VERSION 5.7 ;
BUSBITCHARS "[]" ;
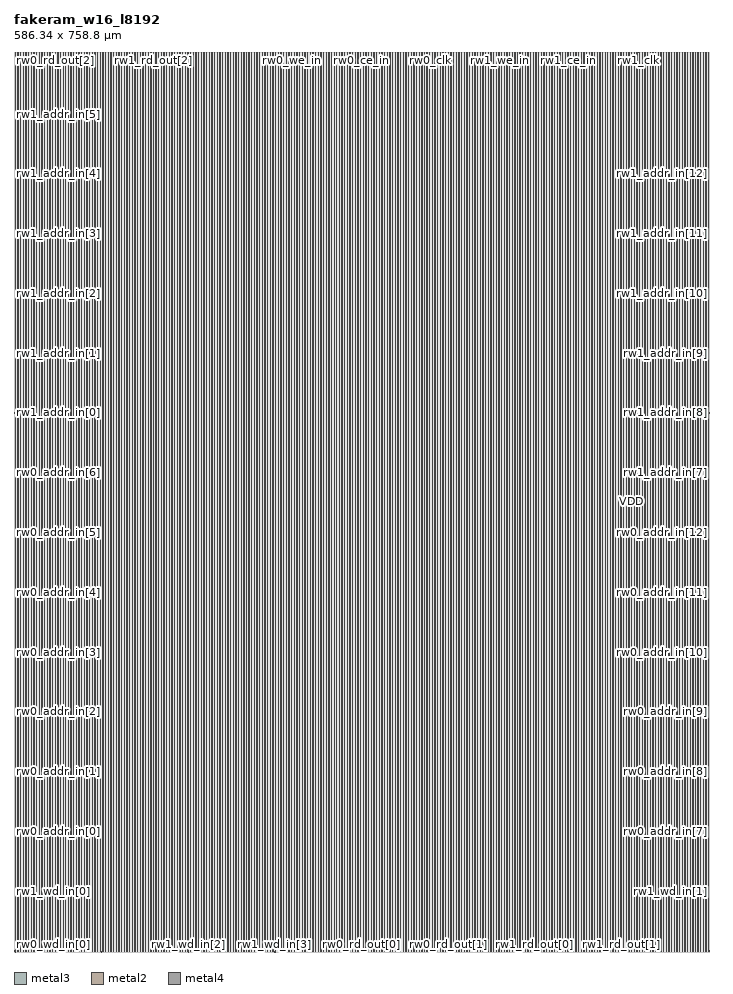
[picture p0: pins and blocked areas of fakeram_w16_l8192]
MACRO fakeram_w16_l8192
  FOREIGN fakeram_w16_l8192 0 0 ;
  SYMMETRY X Y R90 ;
  SIZE 586.340 BY 758.800 ;
  CLASS BLOCK ;
  PIN rw0_wd_in[0]
    DIRECTION INPUT ;
    USE SIGNAL ;
    SHAPE ABUTMENT ;
    PORT
      LAYER metal3 ;
      RECT 0.000 0.805 0.210 0.875 ;
    END
  END rw0_wd_in[0]
  PIN rw0_wd_in[1]
    DIRECTION INPUT ;
    USE SIGNAL ;
    SHAPE ABUTMENT ;
    PORT
      LAYER metal3 ;
      RECT 586.130 0.805 586.340 0.875 ;
    END
  END rw0_wd_in[1]
  PIN rw0_wd_in[2]
    DIRECTION INPUT ;
    USE SIGNAL ;
    SHAPE ABUTMENT ;
    PORT
      LAYER metal2 ;
      RECT 1.105 0.000 1.175 0.210 ;
    END
  END rw0_wd_in[2]
  PIN rw0_wd_in[3]
    DIRECTION INPUT ;
    USE SIGNAL ;
    SHAPE ABUTMENT ;
    PORT
      LAYER metal2 ;
      RECT 74.065 0.000 74.135 0.210 ;
    END
  END rw0_wd_in[3]
  PIN rw1_wd_in[0]
    DIRECTION INPUT ;
    USE SIGNAL ;
    SHAPE ABUTMENT ;
    PORT
      LAYER metal3 ;
      RECT 0.000 51.205 0.210 51.275 ;
    END
  END rw1_wd_in[0]
  PIN rw1_wd_in[1]
    DIRECTION INPUT ;
    USE SIGNAL ;
    SHAPE ABUTMENT ;
    PORT
      LAYER metal3 ;
      RECT 586.130 51.205 586.340 51.275 ;
    END
  END rw1_wd_in[1]
  PIN rw1_wd_in[2]
    DIRECTION INPUT ;
    USE SIGNAL ;
    SHAPE ABUTMENT ;
    PORT
      LAYER metal2 ;
      RECT 147.025 0.000 147.095 0.210 ;
    END
  END rw1_wd_in[2]
  PIN rw1_wd_in[3]
    DIRECTION INPUT ;
    USE SIGNAL ;
    SHAPE ABUTMENT ;
    PORT
      LAYER metal2 ;
      RECT 219.985 0.000 220.055 0.210 ;
    END
  END rw1_wd_in[3]
  PIN rw0_rd_out[0]
    DIRECTION OUTPUT ;
    USE SIGNAL ;
    SHAPE ABUTMENT ;
    PORT
      LAYER metal2 ;
      RECT 292.945 0.000 293.015 0.210 ;
    END
  END rw0_rd_out[0]
  PIN rw0_rd_out[1]
    DIRECTION OUTPUT ;
    USE SIGNAL ;
    SHAPE ABUTMENT ;
    PORT
      LAYER metal2 ;
      RECT 365.905 0.000 365.975 0.210 ;
    END
  END rw0_rd_out[1]
  PIN rw0_rd_out[2]
    DIRECTION OUTPUT ;
    USE SIGNAL ;
    SHAPE ABUTMENT ;
    PORT
      LAYER metal2 ;
      RECT 1.105 758.590 1.175 758.800 ;
    END
  END rw0_rd_out[2]
  PIN rw0_rd_out[3]
    DIRECTION OUTPUT ;
    USE SIGNAL ;
    SHAPE ABUTMENT ;
    PORT
      LAYER metal2 ;
      RECT 59.435 758.590 59.505 758.800 ;
    END
  END rw0_rd_out[3]
  PIN rw1_rd_out[0]
    DIRECTION OUTPUT ;
    USE SIGNAL ;
    SHAPE ABUTMENT ;
    PORT
      LAYER metal2 ;
      RECT 438.865 0.000 438.935 0.210 ;
    END
  END rw1_rd_out[0]
  PIN rw1_rd_out[1]
    DIRECTION OUTPUT ;
    USE SIGNAL ;
    SHAPE ABUTMENT ;
    PORT
      LAYER metal2 ;
      RECT 511.825 0.000 511.895 0.210 ;
    END
  END rw1_rd_out[1]
  PIN rw1_rd_out[2]
    DIRECTION OUTPUT ;
    USE SIGNAL ;
    SHAPE ABUTMENT ;
    PORT
      LAYER metal2 ;
      RECT 117.765 758.590 117.835 758.800 ;
    END
  END rw1_rd_out[2]
  PIN rw1_rd_out[3]
    DIRECTION OUTPUT ;
    USE SIGNAL ;
    SHAPE ABUTMENT ;
    PORT
      LAYER metal2 ;
      RECT 176.095 758.590 176.165 758.800 ;
    END
  END rw1_rd_out[3]
  PIN rw0_addr_in[0]
    DIRECTION INPUT ;
    USE SIGNAL ;
    SHAPE ABUTMENT ;
    PORT
      LAYER metal3 ;
      RECT 0.000 101.605 0.210 101.675 ;
    END
  END rw0_addr_in[0]
  PIN rw0_addr_in[1]
    DIRECTION INPUT ;
    USE SIGNAL ;
    SHAPE ABUTMENT ;
    PORT
      LAYER metal3 ;
      RECT 0.000 152.005 0.210 152.075 ;
    END
  END rw0_addr_in[1]
  PIN rw0_addr_in[2]
    DIRECTION INPUT ;
    USE SIGNAL ;
    SHAPE ABUTMENT ;
    PORT
      LAYER metal3 ;
      RECT 0.000 202.405 0.210 202.475 ;
    END
  END rw0_addr_in[2]
  PIN rw0_addr_in[3]
    DIRECTION INPUT ;
    USE SIGNAL ;
    SHAPE ABUTMENT ;
    PORT
      LAYER metal3 ;
      RECT 0.000 252.805 0.210 252.875 ;
    END
  END rw0_addr_in[3]
  PIN rw0_addr_in[4]
    DIRECTION INPUT ;
    USE SIGNAL ;
    SHAPE ABUTMENT ;
    PORT
      LAYER metal3 ;
      RECT 0.000 303.205 0.210 303.275 ;
    END
  END rw0_addr_in[4]
  PIN rw0_addr_in[5]
    DIRECTION INPUT ;
    USE SIGNAL ;
    SHAPE ABUTMENT ;
    PORT
      LAYER metal3 ;
      RECT 0.000 353.605 0.210 353.675 ;
    END
  END rw0_addr_in[5]
  PIN rw0_addr_in[6]
    DIRECTION INPUT ;
    USE SIGNAL ;
    SHAPE ABUTMENT ;
    PORT
      LAYER metal3 ;
      RECT 0.000 404.005 0.210 404.075 ;
    END
  END rw0_addr_in[6]
  PIN rw0_addr_in[7]
    DIRECTION INPUT ;
    USE SIGNAL ;
    SHAPE ABUTMENT ;
    PORT
      LAYER metal3 ;
      RECT 586.130 101.605 586.340 101.675 ;
    END
  END rw0_addr_in[7]
  PIN rw0_addr_in[8]
    DIRECTION INPUT ;
    USE SIGNAL ;
    SHAPE ABUTMENT ;
    PORT
      LAYER metal3 ;
      RECT 586.130 152.005 586.340 152.075 ;
    END
  END rw0_addr_in[8]
  PIN rw0_addr_in[9]
    DIRECTION INPUT ;
    USE SIGNAL ;
    SHAPE ABUTMENT ;
    PORT
      LAYER metal3 ;
      RECT 586.130 202.405 586.340 202.475 ;
    END
  END rw0_addr_in[9]
  PIN rw0_addr_in[10]
    DIRECTION INPUT ;
    USE SIGNAL ;
    SHAPE ABUTMENT ;
    PORT
      LAYER metal3 ;
      RECT 586.130 252.805 586.340 252.875 ;
    END
  END rw0_addr_in[10]
  PIN rw0_addr_in[11]
    DIRECTION INPUT ;
    USE SIGNAL ;
    SHAPE ABUTMENT ;
    PORT
      LAYER metal3 ;
      RECT 586.130 303.205 586.340 303.275 ;
    END
  END rw0_addr_in[11]
  PIN rw0_addr_in[12]
    DIRECTION INPUT ;
    USE SIGNAL ;
    SHAPE ABUTMENT ;
    PORT
      LAYER metal3 ;
      RECT 586.130 353.605 586.340 353.675 ;
    END
  END rw0_addr_in[12]
  PIN rw1_addr_in[0]
    DIRECTION INPUT ;
    USE SIGNAL ;
    SHAPE ABUTMENT ;
    PORT
      LAYER metal3 ;
      RECT 0.000 454.405 0.210 454.475 ;
    END
  END rw1_addr_in[0]
  PIN rw1_addr_in[1]
    DIRECTION INPUT ;
    USE SIGNAL ;
    SHAPE ABUTMENT ;
    PORT
      LAYER metal3 ;
      RECT 0.000 504.805 0.210 504.875 ;
    END
  END rw1_addr_in[1]
  PIN rw1_addr_in[2]
    DIRECTION INPUT ;
    USE SIGNAL ;
    SHAPE ABUTMENT ;
    PORT
      LAYER metal3 ;
      RECT 0.000 555.205 0.210 555.275 ;
    END
  END rw1_addr_in[2]
  PIN rw1_addr_in[3]
    DIRECTION INPUT ;
    USE SIGNAL ;
    SHAPE ABUTMENT ;
    PORT
      LAYER metal3 ;
      RECT 0.000 605.605 0.210 605.675 ;
    END
  END rw1_addr_in[3]
  PIN rw1_addr_in[4]
    DIRECTION INPUT ;
    USE SIGNAL ;
    SHAPE ABUTMENT ;
    PORT
      LAYER metal3 ;
      RECT 0.000 656.005 0.210 656.075 ;
    END
  END rw1_addr_in[4]
  PIN rw1_addr_in[5]
    DIRECTION INPUT ;
    USE SIGNAL ;
    SHAPE ABUTMENT ;
    PORT
      LAYER metal3 ;
      RECT 0.000 706.405 0.210 706.475 ;
    END
  END rw1_addr_in[5]
  PIN rw1_addr_in[6]
    DIRECTION INPUT ;
    USE SIGNAL ;
    SHAPE ABUTMENT ;
    PORT
      LAYER metal3 ;
      RECT 0.000 756.805 0.210 756.875 ;
    END
  END rw1_addr_in[6]
  PIN rw1_addr_in[7]
    DIRECTION INPUT ;
    USE SIGNAL ;
    SHAPE ABUTMENT ;
    PORT
      LAYER metal3 ;
      RECT 586.130 404.005 586.340 404.075 ;
    END
  END rw1_addr_in[7]
  PIN rw1_addr_in[8]
    DIRECTION INPUT ;
    USE SIGNAL ;
    SHAPE ABUTMENT ;
    PORT
      LAYER metal3 ;
      RECT 586.130 454.405 586.340 454.475 ;
    END
  END rw1_addr_in[8]
  PIN rw1_addr_in[9]
    DIRECTION INPUT ;
    USE SIGNAL ;
    SHAPE ABUTMENT ;
    PORT
      LAYER metal3 ;
      RECT 586.130 504.805 586.340 504.875 ;
    END
  END rw1_addr_in[9]
  PIN rw1_addr_in[10]
    DIRECTION INPUT ;
    USE SIGNAL ;
    SHAPE ABUTMENT ;
    PORT
      LAYER metal3 ;
      RECT 586.130 555.205 586.340 555.275 ;
    END
  END rw1_addr_in[10]
  PIN rw1_addr_in[11]
    DIRECTION INPUT ;
    USE SIGNAL ;
    SHAPE ABUTMENT ;
    PORT
      LAYER metal3 ;
      RECT 586.130 605.605 586.340 605.675 ;
    END
  END rw1_addr_in[11]
  PIN rw1_addr_in[12]
    DIRECTION INPUT ;
    USE SIGNAL ;
    SHAPE ABUTMENT ;
    PORT
      LAYER metal3 ;
      RECT 586.130 656.005 586.340 656.075 ;
    END
  END rw1_addr_in[12]
  PIN rw0_we_in
    DIRECTION INPUT ;
    USE SIGNAL ;
    SHAPE ABUTMENT ;
    PORT
      LAYER metal2 ;
      RECT 234.425 758.590 234.495 758.800 ;
    END
  END rw0_we_in
  PIN rw0_ce_in
    DIRECTION INPUT ;
    USE SIGNAL ;
    SHAPE ABUTMENT ;
    PORT
      LAYER metal2 ;
      RECT 292.755 758.590 292.825 758.800 ;
    END
  END rw0_ce_in
  PIN rw0_clk
    DIRECTION INPUT ;
    USE SIGNAL ;
    SHAPE ABUTMENT ;
    PORT
      LAYER metal2 ;
      RECT 351.085 758.590 351.155 758.800 ;
    END
  END rw0_clk
  PIN rw1_we_in
    DIRECTION INPUT ;
    USE SIGNAL ;
    SHAPE ABUTMENT ;
    PORT
      LAYER metal2 ;
      RECT 409.415 758.590 409.485 758.800 ;
    END
  END rw1_we_in
  PIN rw1_ce_in
    DIRECTION INPUT ;
    USE SIGNAL ;
    SHAPE ABUTMENT ;
    PORT
      LAYER metal2 ;
      RECT 467.745 758.590 467.815 758.800 ;
    END
  END rw1_ce_in
  PIN rw1_clk
    DIRECTION INPUT ;
    USE SIGNAL ;
    SHAPE ABUTMENT ;
    PORT
      LAYER metal2 ;
      RECT 526.075 758.590 526.145 758.800 ;
    END
  END rw1_clk
  PIN VSS
    DIRECTION INOUT ;
    USE GROUND ;
    PORT
      LAYER metal4 ;
      RECT 1.000 0.840 1.280 757.960 ;
      RECT 3.240 0.840 3.520 757.960 ;
      RECT 5.480 0.840 5.760 757.960 ;
      RECT 7.720 0.840 8.000 757.960 ;
      RECT 9.960 0.840 10.240 757.960 ;
      RECT 12.200 0.840 12.480 757.960 ;
      RECT 14.440 0.840 14.720 757.960 ;
      RECT 16.680 0.840 16.960 757.960 ;
      RECT 18.920 0.840 19.200 757.960 ;
      RECT 21.160 0.840 21.440 757.960 ;
      RECT 23.400 0.840 23.680 757.960 ;
      RECT 25.640 0.840 25.920 757.960 ;
      RECT 27.880 0.840 28.160 757.960 ;
      RECT 30.120 0.840 30.400 757.960 ;
      RECT 32.360 0.840 32.640 757.960 ;
      RECT 34.600 0.840 34.880 757.960 ;
      RECT 36.840 0.840 37.120 757.960 ;
      RECT 39.080 0.840 39.360 757.960 ;
      RECT 41.320 0.840 41.600 757.960 ;
      RECT 43.560 0.840 43.840 757.960 ;
      RECT 45.800 0.840 46.080 757.960 ;
      RECT 48.040 0.840 48.320 757.960 ;
      RECT 50.280 0.840 50.560 757.960 ;
      RECT 52.520 0.840 52.800 757.960 ;
      RECT 54.760 0.840 55.040 757.960 ;
      RECT 57.000 0.840 57.280 757.960 ;
      RECT 59.240 0.840 59.520 757.960 ;
      RECT 61.480 0.840 61.760 757.960 ;
      RECT 63.720 0.840 64.000 757.960 ;
      RECT 65.960 0.840 66.240 757.960 ;
      RECT 68.200 0.840 68.480 757.960 ;
      RECT 70.440 0.840 70.720 757.960 ;
      RECT 72.680 0.840 72.960 757.960 ;
      RECT 74.920 0.840 75.200 757.960 ;
      RECT 77.160 0.840 77.440 757.960 ;
      RECT 79.400 0.840 79.680 757.960 ;
      RECT 81.640 0.840 81.920 757.960 ;
      RECT 83.880 0.840 84.160 757.960 ;
      RECT 86.120 0.840 86.400 757.960 ;
      RECT 88.360 0.840 88.640 757.960 ;
      RECT 90.600 0.840 90.880 757.960 ;
      RECT 92.840 0.840 93.120 757.960 ;
      RECT 95.080 0.840 95.360 757.960 ;
      RECT 97.320 0.840 97.600 757.960 ;
      RECT 99.560 0.840 99.840 757.960 ;
      RECT 101.800 0.840 102.080 757.960 ;
      RECT 104.040 0.840 104.320 757.960 ;
      RECT 106.280 0.840 106.560 757.960 ;
      RECT 108.520 0.840 108.800 757.960 ;
      RECT 110.760 0.840 111.040 757.960 ;
      RECT 113.000 0.840 113.280 757.960 ;
      RECT 115.240 0.840 115.520 757.960 ;
      RECT 117.480 0.840 117.760 757.960 ;
      RECT 119.720 0.840 120.000 757.960 ;
      RECT 121.960 0.840 122.240 757.960 ;
      RECT 124.200 0.840 124.480 757.960 ;
      RECT 126.440 0.840 126.720 757.960 ;
      RECT 128.680 0.840 128.960 757.960 ;
      RECT 130.920 0.840 131.200 757.960 ;
      RECT 133.160 0.840 133.440 757.960 ;
      RECT 135.400 0.840 135.680 757.960 ;
      RECT 137.640 0.840 137.920 757.960 ;
      RECT 139.880 0.840 140.160 757.960 ;
      RECT 142.120 0.840 142.400 757.960 ;
      RECT 144.360 0.840 144.640 757.960 ;
      RECT 146.600 0.840 146.880 757.960 ;
      RECT 148.840 0.840 149.120 757.960 ;
      RECT 151.080 0.840 151.360 757.960 ;
      RECT 153.320 0.840 153.600 757.960 ;
      RECT 155.560 0.840 155.840 757.960 ;
      RECT 157.800 0.840 158.080 757.960 ;
      RECT 160.040 0.840 160.320 757.960 ;
      RECT 162.280 0.840 162.560 757.960 ;
      RECT 164.520 0.840 164.800 757.960 ;
      RECT 166.760 0.840 167.040 757.960 ;
      RECT 169.000 0.840 169.280 757.960 ;
      RECT 171.240 0.840 171.520 757.960 ;
      RECT 173.480 0.840 173.760 757.960 ;
      RECT 175.720 0.840 176.000 757.960 ;
      RECT 177.960 0.840 178.240 757.960 ;
      RECT 180.200 0.840 180.480 757.960 ;
      RECT 182.440 0.840 182.720 757.960 ;
      RECT 184.680 0.840 184.960 757.960 ;
      RECT 186.920 0.840 187.200 757.960 ;
      RECT 189.160 0.840 189.440 757.960 ;
      RECT 191.400 0.840 191.680 757.960 ;
      RECT 193.640 0.840 193.920 757.960 ;
      RECT 195.880 0.840 196.160 757.960 ;
      RECT 198.120 0.840 198.400 757.960 ;
      RECT 200.360 0.840 200.640 757.960 ;
      RECT 202.600 0.840 202.880 757.960 ;
      RECT 204.840 0.840 205.120 757.960 ;
      RECT 207.080 0.840 207.360 757.960 ;
      RECT 209.320 0.840 209.600 757.960 ;
      RECT 211.560 0.840 211.840 757.960 ;
      RECT 213.800 0.840 214.080 757.960 ;
      RECT 216.040 0.840 216.320 757.960 ;
      RECT 218.280 0.840 218.560 757.960 ;
      RECT 220.520 0.840 220.800 757.960 ;
      RECT 222.760 0.840 223.040 757.960 ;
      RECT 225.000 0.840 225.280 757.960 ;
      RECT 227.240 0.840 227.520 757.960 ;
      RECT 229.480 0.840 229.760 757.960 ;
      RECT 231.720 0.840 232.000 757.960 ;
      RECT 233.960 0.840 234.240 757.960 ;
      RECT 236.200 0.840 236.480 757.960 ;
      RECT 238.440 0.840 238.720 757.960 ;
      RECT 240.680 0.840 240.960 757.960 ;
      RECT 242.920 0.840 243.200 757.960 ;
      RECT 245.160 0.840 245.440 757.960 ;
      RECT 247.400 0.840 247.680 757.960 ;
      RECT 249.640 0.840 249.920 757.960 ;
      RECT 251.880 0.840 252.160 757.960 ;
      RECT 254.120 0.840 254.400 757.960 ;
      RECT 256.360 0.840 256.640 757.960 ;
      RECT 258.600 0.840 258.880 757.960 ;
      RECT 260.840 0.840 261.120 757.960 ;
      RECT 263.080 0.840 263.360 757.960 ;
      RECT 265.320 0.840 265.600 757.960 ;
      RECT 267.560 0.840 267.840 757.960 ;
      RECT 269.800 0.840 270.080 757.960 ;
      RECT 272.040 0.840 272.320 757.960 ;
      RECT 274.280 0.840 274.560 757.960 ;
      RECT 276.520 0.840 276.800 757.960 ;
      RECT 278.760 0.840 279.040 757.960 ;
      RECT 281.000 0.840 281.280 757.960 ;
      RECT 283.240 0.840 283.520 757.960 ;
      RECT 285.480 0.840 285.760 757.960 ;
      RECT 287.720 0.840 288.000 757.960 ;
      RECT 289.960 0.840 290.240 757.960 ;
      RECT 292.200 0.840 292.480 757.960 ;
      RECT 294.440 0.840 294.720 757.960 ;
      RECT 296.680 0.840 296.960 757.960 ;
      RECT 298.920 0.840 299.200 757.960 ;
      RECT 301.160 0.840 301.440 757.960 ;
      RECT 303.400 0.840 303.680 757.960 ;
      RECT 305.640 0.840 305.920 757.960 ;
      RECT 307.880 0.840 308.160 757.960 ;
      RECT 310.120 0.840 310.400 757.960 ;
      RECT 312.360 0.840 312.640 757.960 ;
      RECT 314.600 0.840 314.880 757.960 ;
      RECT 316.840 0.840 317.120 757.960 ;
      RECT 319.080 0.840 319.360 757.960 ;
      RECT 321.320 0.840 321.600 757.960 ;
      RECT 323.560 0.840 323.840 757.960 ;
      RECT 325.800 0.840 326.080 757.960 ;
      RECT 328.040 0.840 328.320 757.960 ;
      RECT 330.280 0.840 330.560 757.960 ;
      RECT 332.520 0.840 332.800 757.960 ;
      RECT 334.760 0.840 335.040 757.960 ;
      RECT 337.000 0.840 337.280 757.960 ;
      RECT 339.240 0.840 339.520 757.960 ;
      RECT 341.480 0.840 341.760 757.960 ;
      RECT 343.720 0.840 344.000 757.960 ;
      RECT 345.960 0.840 346.240 757.960 ;
      RECT 348.200 0.840 348.480 757.960 ;
      RECT 350.440 0.840 350.720 757.960 ;
      RECT 352.680 0.840 352.960 757.960 ;
      RECT 354.920 0.840 355.200 757.960 ;
      RECT 357.160 0.840 357.440 757.960 ;
      RECT 359.400 0.840 359.680 757.960 ;
      RECT 361.640 0.840 361.920 757.960 ;
      RECT 363.880 0.840 364.160 757.960 ;
      RECT 366.120 0.840 366.400 757.960 ;
      RECT 368.360 0.840 368.640 757.960 ;
      RECT 370.600 0.840 370.880 757.960 ;
      RECT 372.840 0.840 373.120 757.960 ;
      RECT 375.080 0.840 375.360 757.960 ;
      RECT 377.320 0.840 377.600 757.960 ;
      RECT 379.560 0.840 379.840 757.960 ;
      RECT 381.800 0.840 382.080 757.960 ;
      RECT 384.040 0.840 384.320 757.960 ;
      RECT 386.280 0.840 386.560 757.960 ;
      RECT 388.520 0.840 388.800 757.960 ;
      RECT 390.760 0.840 391.040 757.960 ;
      RECT 393.000 0.840 393.280 757.960 ;
      RECT 395.240 0.840 395.520 757.960 ;
      RECT 397.480 0.840 397.760 757.960 ;
      RECT 399.720 0.840 400.000 757.960 ;
      RECT 401.960 0.840 402.240 757.960 ;
      RECT 404.200 0.840 404.480 757.960 ;
      RECT 406.440 0.840 406.720 757.960 ;
      RECT 408.680 0.840 408.960 757.960 ;
      RECT 410.920 0.840 411.200 757.960 ;
      RECT 413.160 0.840 413.440 757.960 ;
      RECT 415.400 0.840 415.680 757.960 ;
      RECT 417.640 0.840 417.920 757.960 ;
      RECT 419.880 0.840 420.160 757.960 ;
      RECT 422.120 0.840 422.400 757.960 ;
      RECT 424.360 0.840 424.640 757.960 ;
      RECT 426.600 0.840 426.880 757.960 ;
      RECT 428.840 0.840 429.120 757.960 ;
      RECT 431.080 0.840 431.360 757.960 ;
      RECT 433.320 0.840 433.600 757.960 ;
      RECT 435.560 0.840 435.840 757.960 ;
      RECT 437.800 0.840 438.080 757.960 ;
      RECT 440.040 0.840 440.320 757.960 ;
      RECT 442.280 0.840 442.560 757.960 ;
      RECT 444.520 0.840 444.800 757.960 ;
      RECT 446.760 0.840 447.040 757.960 ;
      RECT 449.000 0.840 449.280 757.960 ;
      RECT 451.240 0.840 451.520 757.960 ;
      RECT 453.480 0.840 453.760 757.960 ;
      RECT 455.720 0.840 456.000 757.960 ;
      RECT 457.960 0.840 458.240 757.960 ;
      RECT 460.200 0.840 460.480 757.960 ;
      RECT 462.440 0.840 462.720 757.960 ;
      RECT 464.680 0.840 464.960 757.960 ;
      RECT 466.920 0.840 467.200 757.960 ;
      RECT 469.160 0.840 469.440 757.960 ;
      RECT 471.400 0.840 471.680 757.960 ;
      RECT 473.640 0.840 473.920 757.960 ;
      RECT 475.880 0.840 476.160 757.960 ;
      RECT 478.120 0.840 478.400 757.960 ;
      RECT 480.360 0.840 480.640 757.960 ;
      RECT 482.600 0.840 482.880 757.960 ;
      RECT 484.840 0.840 485.120 757.960 ;
      RECT 487.080 0.840 487.360 757.960 ;
      RECT 489.320 0.840 489.600 757.960 ;
      RECT 491.560 0.840 491.840 757.960 ;
      RECT 493.800 0.840 494.080 757.960 ;
      RECT 496.040 0.840 496.320 757.960 ;
      RECT 498.280 0.840 498.560 757.960 ;
      RECT 500.520 0.840 500.800 757.960 ;
      RECT 502.760 0.840 503.040 757.960 ;
      RECT 505.000 0.840 505.280 757.960 ;
      RECT 507.240 0.840 507.520 757.960 ;
      RECT 509.480 0.840 509.760 757.960 ;
      RECT 511.720 0.840 512.000 757.960 ;
      RECT 513.960 0.840 514.240 757.960 ;
      RECT 516.200 0.840 516.480 757.960 ;
      RECT 518.440 0.840 518.720 757.960 ;
      RECT 520.680 0.840 520.960 757.960 ;
      RECT 522.920 0.840 523.200 757.960 ;
      RECT 525.160 0.840 525.440 757.960 ;
      RECT 527.400 0.840 527.680 757.960 ;
      RECT 529.640 0.840 529.920 757.960 ;
      RECT 531.880 0.840 532.160 757.960 ;
      RECT 534.120 0.840 534.400 757.960 ;
      RECT 536.360 0.840 536.640 757.960 ;
      RECT 538.600 0.840 538.880 757.960 ;
      RECT 540.840 0.840 541.120 757.960 ;
      RECT 543.080 0.840 543.360 757.960 ;
      RECT 545.320 0.840 545.600 757.960 ;
      RECT 547.560 0.840 547.840 757.960 ;
      RECT 549.800 0.840 550.080 757.960 ;
      RECT 552.040 0.840 552.320 757.960 ;
      RECT 554.280 0.840 554.560 757.960 ;
      RECT 556.520 0.840 556.800 757.960 ;
      RECT 558.760 0.840 559.040 757.960 ;
      RECT 561.000 0.840 561.280 757.960 ;
      RECT 563.240 0.840 563.520 757.960 ;
      RECT 565.480 0.840 565.760 757.960 ;
      RECT 567.720 0.840 568.000 757.960 ;
      RECT 569.960 0.840 570.240 757.960 ;
      RECT 572.200 0.840 572.480 757.960 ;
      RECT 574.440 0.840 574.720 757.960 ;
      RECT 576.680 0.840 576.960 757.960 ;
      RECT 578.920 0.840 579.200 757.960 ;
      RECT 581.160 0.840 581.440 757.960 ;
      RECT 583.400 0.840 583.680 757.960 ;
      RECT 585.640 0.840 585.920 757.960 ;
    END
  END VSS
  PIN VDD
    DIRECTION INOUT ;
    USE POWER ;
    PORT
      LAYER metal4 ;
      RECT 1.000 0.840 1.280 757.960 ;
      RECT 3.240 0.840 3.520 757.960 ;
      RECT 5.480 0.840 5.760 757.960 ;
      RECT 7.720 0.840 8.000 757.960 ;
      RECT 9.960 0.840 10.240 757.960 ;
      RECT 12.200 0.840 12.480 757.960 ;
      RECT 14.440 0.840 14.720 757.960 ;
      RECT 16.680 0.840 16.960 757.960 ;
      RECT 18.920 0.840 19.200 757.960 ;
      RECT 21.160 0.840 21.440 757.960 ;
      RECT 23.400 0.840 23.680 757.960 ;
      RECT 25.640 0.840 25.920 757.960 ;
      RECT 27.880 0.840 28.160 757.960 ;
      RECT 30.120 0.840 30.400 757.960 ;
      RECT 32.360 0.840 32.640 757.960 ;
      RECT 34.600 0.840 34.880 757.960 ;
      RECT 36.840 0.840 37.120 757.960 ;
      RECT 39.080 0.840 39.360 757.960 ;
      RECT 41.320 0.840 41.600 757.960 ;
      RECT 43.560 0.840 43.840 757.960 ;
      RECT 45.800 0.840 46.080 757.960 ;
      RECT 48.040 0.840 48.320 757.960 ;
      RECT 50.280 0.840 50.560 757.960 ;
      RECT 52.520 0.840 52.800 757.960 ;
      RECT 54.760 0.840 55.040 757.960 ;
      RECT 57.000 0.840 57.280 757.960 ;
      RECT 59.240 0.840 59.520 757.960 ;
      RECT 61.480 0.840 61.760 757.960 ;
      RECT 63.720 0.840 64.000 757.960 ;
      RECT 65.960 0.840 66.240 757.960 ;
      RECT 68.200 0.840 68.480 757.960 ;
      RECT 70.440 0.840 70.720 757.960 ;
      RECT 72.680 0.840 72.960 757.960 ;
      RECT 74.920 0.840 75.200 757.960 ;
      RECT 77.160 0.840 77.440 757.960 ;
      RECT 79.400 0.840 79.680 757.960 ;
      RECT 81.640 0.840 81.920 757.960 ;
      RECT 83.880 0.840 84.160 757.960 ;
      RECT 86.120 0.840 86.400 757.960 ;
      RECT 88.360 0.840 88.640 757.960 ;
      RECT 90.600 0.840 90.880 757.960 ;
      RECT 92.840 0.840 93.120 757.960 ;
      RECT 95.080 0.840 95.360 757.960 ;
      RECT 97.320 0.840 97.600 757.960 ;
      RECT 99.560 0.840 99.840 757.960 ;
      RECT 101.800 0.840 102.080 757.960 ;
      RECT 104.040 0.840 104.320 757.960 ;
      RECT 106.280 0.840 106.560 757.960 ;
      RECT 108.520 0.840 108.800 757.960 ;
      RECT 110.760 0.840 111.040 757.960 ;
      RECT 113.000 0.840 113.280 757.960 ;
      RECT 115.240 0.840 115.520 757.960 ;
      RECT 117.480 0.840 117.760 757.960 ;
      RECT 119.720 0.840 120.000 757.960 ;
      RECT 121.960 0.840 122.240 757.960 ;
      RECT 124.200 0.840 124.480 757.960 ;
      RECT 126.440 0.840 126.720 757.960 ;
      RECT 128.680 0.840 128.960 757.960 ;
      RECT 130.920 0.840 131.200 757.960 ;
      RECT 133.160 0.840 133.440 757.960 ;
      RECT 135.400 0.840 135.680 757.960 ;
      RECT 137.640 0.840 137.920 757.960 ;
      RECT 139.880 0.840 140.160 757.960 ;
      RECT 142.120 0.840 142.400 757.960 ;
      RECT 144.360 0.840 144.640 757.960 ;
      RECT 146.600 0.840 146.880 757.960 ;
      RECT 148.840 0.840 149.120 757.960 ;
      RECT 151.080 0.840 151.360 757.960 ;
      RECT 153.320 0.840 153.600 757.960 ;
      RECT 155.560 0.840 155.840 757.960 ;
      RECT 157.800 0.840 158.080 757.960 ;
      RECT 160.040 0.840 160.320 757.960 ;
      RECT 162.280 0.840 162.560 757.960 ;
      RECT 164.520 0.840 164.800 757.960 ;
      RECT 166.760 0.840 167.040 757.960 ;
      RECT 169.000 0.840 169.280 757.960 ;
      RECT 171.240 0.840 171.520 757.960 ;
      RECT 173.480 0.840 173.760 757.960 ;
      RECT 175.720 0.840 176.000 757.960 ;
      RECT 177.960 0.840 178.240 757.960 ;
      RECT 180.200 0.840 180.480 757.960 ;
      RECT 182.440 0.840 182.720 757.960 ;
      RECT 184.680 0.840 184.960 757.960 ;
      RECT 186.920 0.840 187.200 757.960 ;
      RECT 189.160 0.840 189.440 757.960 ;
      RECT 191.400 0.840 191.680 757.960 ;
      RECT 193.640 0.840 193.920 757.960 ;
      RECT 195.880 0.840 196.160 757.960 ;
      RECT 198.120 0.840 198.400 757.960 ;
      RECT 200.360 0.840 200.640 757.960 ;
      RECT 202.600 0.840 202.880 757.960 ;
      RECT 204.840 0.840 205.120 757.960 ;
      RECT 207.080 0.840 207.360 757.960 ;
      RECT 209.320 0.840 209.600 757.960 ;
      RECT 211.560 0.840 211.840 757.960 ;
      RECT 213.800 0.840 214.080 757.960 ;
      RECT 216.040 0.840 216.320 757.960 ;
      RECT 218.280 0.840 218.560 757.960 ;
      RECT 220.520 0.840 220.800 757.960 ;
      RECT 222.760 0.840 223.040 757.960 ;
      RECT 225.000 0.840 225.280 757.960 ;
      RECT 227.240 0.840 227.520 757.960 ;
      RECT 229.480 0.840 229.760 757.960 ;
      RECT 231.720 0.840 232.000 757.960 ;
      RECT 233.960 0.840 234.240 757.960 ;
      RECT 236.200 0.840 236.480 757.960 ;
      RECT 238.440 0.840 238.720 757.960 ;
      RECT 240.680 0.840 240.960 757.960 ;
      RECT 242.920 0.840 243.200 757.960 ;
      RECT 245.160 0.840 245.440 757.960 ;
      RECT 247.400 0.840 247.680 757.960 ;
      RECT 249.640 0.840 249.920 757.960 ;
      RECT 251.880 0.840 252.160 757.960 ;
      RECT 254.120 0.840 254.400 757.960 ;
      RECT 256.360 0.840 256.640 757.960 ;
      RECT 258.600 0.840 258.880 757.960 ;
      RECT 260.840 0.840 261.120 757.960 ;
      RECT 263.080 0.840 263.360 757.960 ;
      RECT 265.320 0.840 265.600 757.960 ;
      RECT 267.560 0.840 267.840 757.960 ;
      RECT 269.800 0.840 270.080 757.960 ;
      RECT 272.040 0.840 272.320 757.960 ;
      RECT 274.280 0.840 274.560 757.960 ;
      RECT 276.520 0.840 276.800 757.960 ;
      RECT 278.760 0.840 279.040 757.960 ;
      RECT 281.000 0.840 281.280 757.960 ;
      RECT 283.240 0.840 283.520 757.960 ;
      RECT 285.480 0.840 285.760 757.960 ;
      RECT 287.720 0.840 288.000 757.960 ;
      RECT 289.960 0.840 290.240 757.960 ;
      RECT 292.200 0.840 292.480 757.960 ;
      RECT 294.440 0.840 294.720 757.960 ;
      RECT 296.680 0.840 296.960 757.960 ;
      RECT 298.920 0.840 299.200 757.960 ;
      RECT 301.160 0.840 301.440 757.960 ;
      RECT 303.400 0.840 303.680 757.960 ;
      RECT 305.640 0.840 305.920 757.960 ;
      RECT 307.880 0.840 308.160 757.960 ;
      RECT 310.120 0.840 310.400 757.960 ;
      RECT 312.360 0.840 312.640 757.960 ;
      RECT 314.600 0.840 314.880 757.960 ;
      RECT 316.840 0.840 317.120 757.960 ;
      RECT 319.080 0.840 319.360 757.960 ;
      RECT 321.320 0.840 321.600 757.960 ;
      RECT 323.560 0.840 323.840 757.960 ;
      RECT 325.800 0.840 326.080 757.960 ;
      RECT 328.040 0.840 328.320 757.960 ;
      RECT 330.280 0.840 330.560 757.960 ;
      RECT 332.520 0.840 332.800 757.960 ;
      RECT 334.760 0.840 335.040 757.960 ;
      RECT 337.000 0.840 337.280 757.960 ;
      RECT 339.240 0.840 339.520 757.960 ;
      RECT 341.480 0.840 341.760 757.960 ;
      RECT 343.720 0.840 344.000 757.960 ;
      RECT 345.960 0.840 346.240 757.960 ;
      RECT 348.200 0.840 348.480 757.960 ;
      RECT 350.440 0.840 350.720 757.960 ;
      RECT 352.680 0.840 352.960 757.960 ;
      RECT 354.920 0.840 355.200 757.960 ;
      RECT 357.160 0.840 357.440 757.960 ;
      RECT 359.400 0.840 359.680 757.960 ;
      RECT 361.640 0.840 361.920 757.960 ;
      RECT 363.880 0.840 364.160 757.960 ;
      RECT 366.120 0.840 366.400 757.960 ;
      RECT 368.360 0.840 368.640 757.960 ;
      RECT 370.600 0.840 370.880 757.960 ;
      RECT 372.840 0.840 373.120 757.960 ;
      RECT 375.080 0.840 375.360 757.960 ;
      RECT 377.320 0.840 377.600 757.960 ;
      RECT 379.560 0.840 379.840 757.960 ;
      RECT 381.800 0.840 382.080 757.960 ;
      RECT 384.040 0.840 384.320 757.960 ;
      RECT 386.280 0.840 386.560 757.960 ;
      RECT 388.520 0.840 388.800 757.960 ;
      RECT 390.760 0.840 391.040 757.960 ;
      RECT 393.000 0.840 393.280 757.960 ;
      RECT 395.240 0.840 395.520 757.960 ;
      RECT 397.480 0.840 397.760 757.960 ;
      RECT 399.720 0.840 400.000 757.960 ;
      RECT 401.960 0.840 402.240 757.960 ;
      RECT 404.200 0.840 404.480 757.960 ;
      RECT 406.440 0.840 406.720 757.960 ;
      RECT 408.680 0.840 408.960 757.960 ;
      RECT 410.920 0.840 411.200 757.960 ;
      RECT 413.160 0.840 413.440 757.960 ;
      RECT 415.400 0.840 415.680 757.960 ;
      RECT 417.640 0.840 417.920 757.960 ;
      RECT 419.880 0.840 420.160 757.960 ;
      RECT 422.120 0.840 422.400 757.960 ;
      RECT 424.360 0.840 424.640 757.960 ;
      RECT 426.600 0.840 426.880 757.960 ;
      RECT 428.840 0.840 429.120 757.960 ;
      RECT 431.080 0.840 431.360 757.960 ;
      RECT 433.320 0.840 433.600 757.960 ;
      RECT 435.560 0.840 435.840 757.960 ;
      RECT 437.800 0.840 438.080 757.960 ;
      RECT 440.040 0.840 440.320 757.960 ;
      RECT 442.280 0.840 442.560 757.960 ;
      RECT 444.520 0.840 444.800 757.960 ;
      RECT 446.760 0.840 447.040 757.960 ;
      RECT 449.000 0.840 449.280 757.960 ;
      RECT 451.240 0.840 451.520 757.960 ;
      RECT 453.480 0.840 453.760 757.960 ;
      RECT 455.720 0.840 456.000 757.960 ;
      RECT 457.960 0.840 458.240 757.960 ;
      RECT 460.200 0.840 460.480 757.960 ;
      RECT 462.440 0.840 462.720 757.960 ;
      RECT 464.680 0.840 464.960 757.960 ;
      RECT 466.920 0.840 467.200 757.960 ;
      RECT 469.160 0.840 469.440 757.960 ;
      RECT 471.400 0.840 471.680 757.960 ;
      RECT 473.640 0.840 473.920 757.960 ;
      RECT 475.880 0.840 476.160 757.960 ;
      RECT 478.120 0.840 478.400 757.960 ;
      RECT 480.360 0.840 480.640 757.960 ;
      RECT 482.600 0.840 482.880 757.960 ;
      RECT 484.840 0.840 485.120 757.960 ;
      RECT 487.080 0.840 487.360 757.960 ;
      RECT 489.320 0.840 489.600 757.960 ;
      RECT 491.560 0.840 491.840 757.960 ;
      RECT 493.800 0.840 494.080 757.960 ;
      RECT 496.040 0.840 496.320 757.960 ;
      RECT 498.280 0.840 498.560 757.960 ;
      RECT 500.520 0.840 500.800 757.960 ;
      RECT 502.760 0.840 503.040 757.960 ;
      RECT 505.000 0.840 505.280 757.960 ;
      RECT 507.240 0.840 507.520 757.960 ;
      RECT 509.480 0.840 509.760 757.960 ;
      RECT 511.720 0.840 512.000 757.960 ;
      RECT 513.960 0.840 514.240 757.960 ;
      RECT 516.200 0.840 516.480 757.960 ;
      RECT 518.440 0.840 518.720 757.960 ;
      RECT 520.680 0.840 520.960 757.960 ;
      RECT 522.920 0.840 523.200 757.960 ;
      RECT 525.160 0.840 525.440 757.960 ;
      RECT 527.400 0.840 527.680 757.960 ;
      RECT 529.640 0.840 529.920 757.960 ;
      RECT 531.880 0.840 532.160 757.960 ;
      RECT 534.120 0.840 534.400 757.960 ;
      RECT 536.360 0.840 536.640 757.960 ;
      RECT 538.600 0.840 538.880 757.960 ;
      RECT 540.840 0.840 541.120 757.960 ;
      RECT 543.080 0.840 543.360 757.960 ;
      RECT 545.320 0.840 545.600 757.960 ;
      RECT 547.560 0.840 547.840 757.960 ;
      RECT 549.800 0.840 550.080 757.960 ;
      RECT 552.040 0.840 552.320 757.960 ;
      RECT 554.280 0.840 554.560 757.960 ;
      RECT 556.520 0.840 556.800 757.960 ;
      RECT 558.760 0.840 559.040 757.960 ;
      RECT 561.000 0.840 561.280 757.960 ;
      RECT 563.240 0.840 563.520 757.960 ;
      RECT 565.480 0.840 565.760 757.960 ;
      RECT 567.720 0.840 568.000 757.960 ;
      RECT 569.960 0.840 570.240 757.960 ;
      RECT 572.200 0.840 572.480 757.960 ;
      RECT 574.440 0.840 574.720 757.960 ;
      RECT 576.680 0.840 576.960 757.960 ;
      RECT 578.920 0.840 579.200 757.960 ;
      RECT 581.160 0.840 581.440 757.960 ;
      RECT 583.400 0.840 583.680 757.960 ;
      RECT 585.640 0.840 585.920 757.960 ;
    END
  END VDD
  OBS
    LAYER metal1 ;
    RECT 0 0 586.340 758.800 ;
    LAYER metal2 ;
    RECT 0 0 586.340 758.800 ;
    LAYER metal3 ;
    RECT 0 0 586.340 758.800 ;
    LAYER metal4 ;
    RECT 0 0 586.340 758.800 ;
    LAYER OVERLAP ;
    RECT 0 0 586.340 758.800 ;
  END
END fakeram_w16_l8192

END LIBRARY
